One B-rep face of a CAD part: STEP entity #131.
In plain terms, the planar face has unit normal (0.653, -0.041, 0.757).
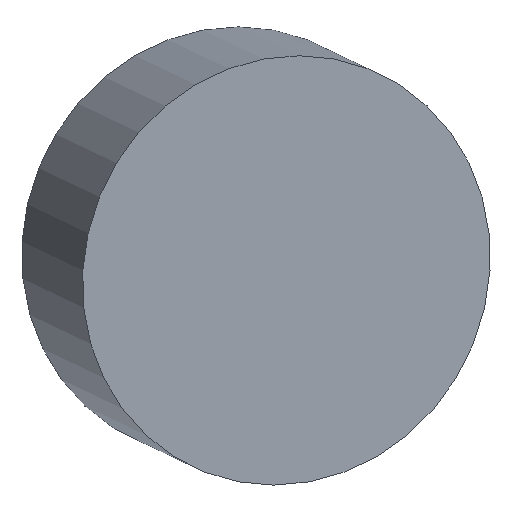
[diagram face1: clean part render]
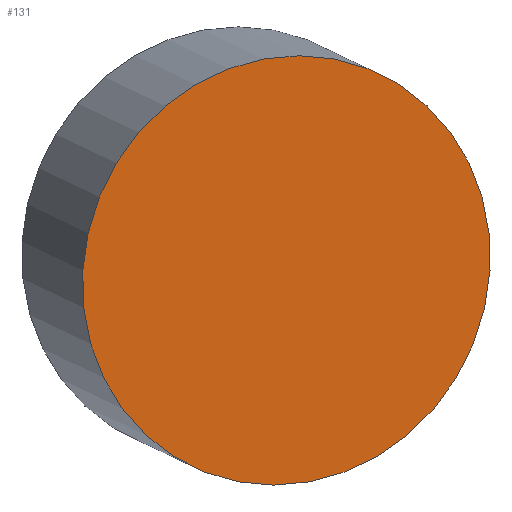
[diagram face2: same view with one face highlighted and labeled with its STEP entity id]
Its self-contained STEP definition (entity closure, numbers rounded to 3 decimals):
#39 = EDGE_CURVE('',#40,#40,#42,.T.);
#40 = VERTEX_POINT('',#41);
#41 = CARTESIAN_POINT('',(-45.275,2.996,19.817)
  );
#42 = SURFACE_CURVE('',#43,(#48,#60),.PCURVE_S1.);
#43 = CIRCLE('',#44,2.5);
#44 = AXIS2_PLACEMENT_3D('',#45,#46,#47);
#45 = CARTESIAN_POINT('',(-43.401,2.722,18.185
    ));
#46 = DIRECTION('',(-0.653,0.041,-0.757)
  );
#47 = DIRECTION('',(-0.75,0.11,0.653));
#48 = PCURVE('',#49,#54);
#49 = CYLINDRICAL_SURFACE('',#50,2.5);
#50 = AXIS2_PLACEMENT_3D('',#51,#52,#53);
#51 = CARTESIAN_POINT('',(-44.706,2.804,16.672)
  );
#52 = DIRECTION('',(0.653,-0.041,0.757));
#53 = DIRECTION('',(-0.75,0.11,0.653));
#54 = DEFINITIONAL_REPRESENTATION('',(#55),#59);
#55 = LINE('',#56,#57);
#56 = CARTESIAN_POINT('',(-0.,2.));
#57 = VECTOR('',#58,1.);
#58 = DIRECTION('',(-1.,0.));
#59 = ( GEOMETRIC_REPRESENTATION_CONTEXT(2) 
PARAMETRIC_REPRESENTATION_CONTEXT() REPRESENTATION_CONTEXT('2D SPACE',''
  ) );
#60 = PCURVE('',#61,#66);
#61 = PLANE('',#62);
#62 = AXIS2_PLACEMENT_3D('',#63,#64,#65);
#63 = CARTESIAN_POINT('',(-43.401,2.722,18.185
    ));
#64 = DIRECTION('',(0.653,-0.041,0.757));
#65 = DIRECTION('',(0.75,-0.11,-0.653));
#66 = DEFINITIONAL_REPRESENTATION('',(#67),#75);
#67 = ( BOUNDED_CURVE() B_SPLINE_CURVE(2,(#68,#69,#70,#71,#72,#73,#74),
.UNSPECIFIED.,.T.,.F.) B_SPLINE_CURVE_WITH_KNOTS((1,2,2,2,2,1),(
    -2.094,0.,2.094,4.189,6.283,
8.378),.UNSPECIFIED.) CURVE() GEOMETRIC_REPRESENTATION_ITEM() 
RATIONAL_B_SPLINE_CURVE((1.,0.5,1.,0.5,1.,0.5,1.)) REPRESENTATION_ITEM(
  '') );
#68 = CARTESIAN_POINT('',(-2.5,0.));
#69 = CARTESIAN_POINT('',(-2.5,4.33));
#70 = CARTESIAN_POINT('',(1.25,2.165));
#71 = CARTESIAN_POINT('',(5.,0.));
#72 = CARTESIAN_POINT('',(1.25,-2.165));
#73 = CARTESIAN_POINT('',(-2.5,-4.33));
#74 = CARTESIAN_POINT('',(-2.5,0.));
#75 = ( GEOMETRIC_REPRESENTATION_CONTEXT(2) 
PARAMETRIC_REPRESENTATION_CONTEXT() REPRESENTATION_CONTEXT('2D SPACE',''
  ) );
#131 = ADVANCED_FACE('',(#132),#61,.T.);
#132 = FACE_BOUND('',#133,.F.);
#133 = EDGE_LOOP('',(#134));
#134 = ORIENTED_EDGE('',*,*,#39,.T.);
